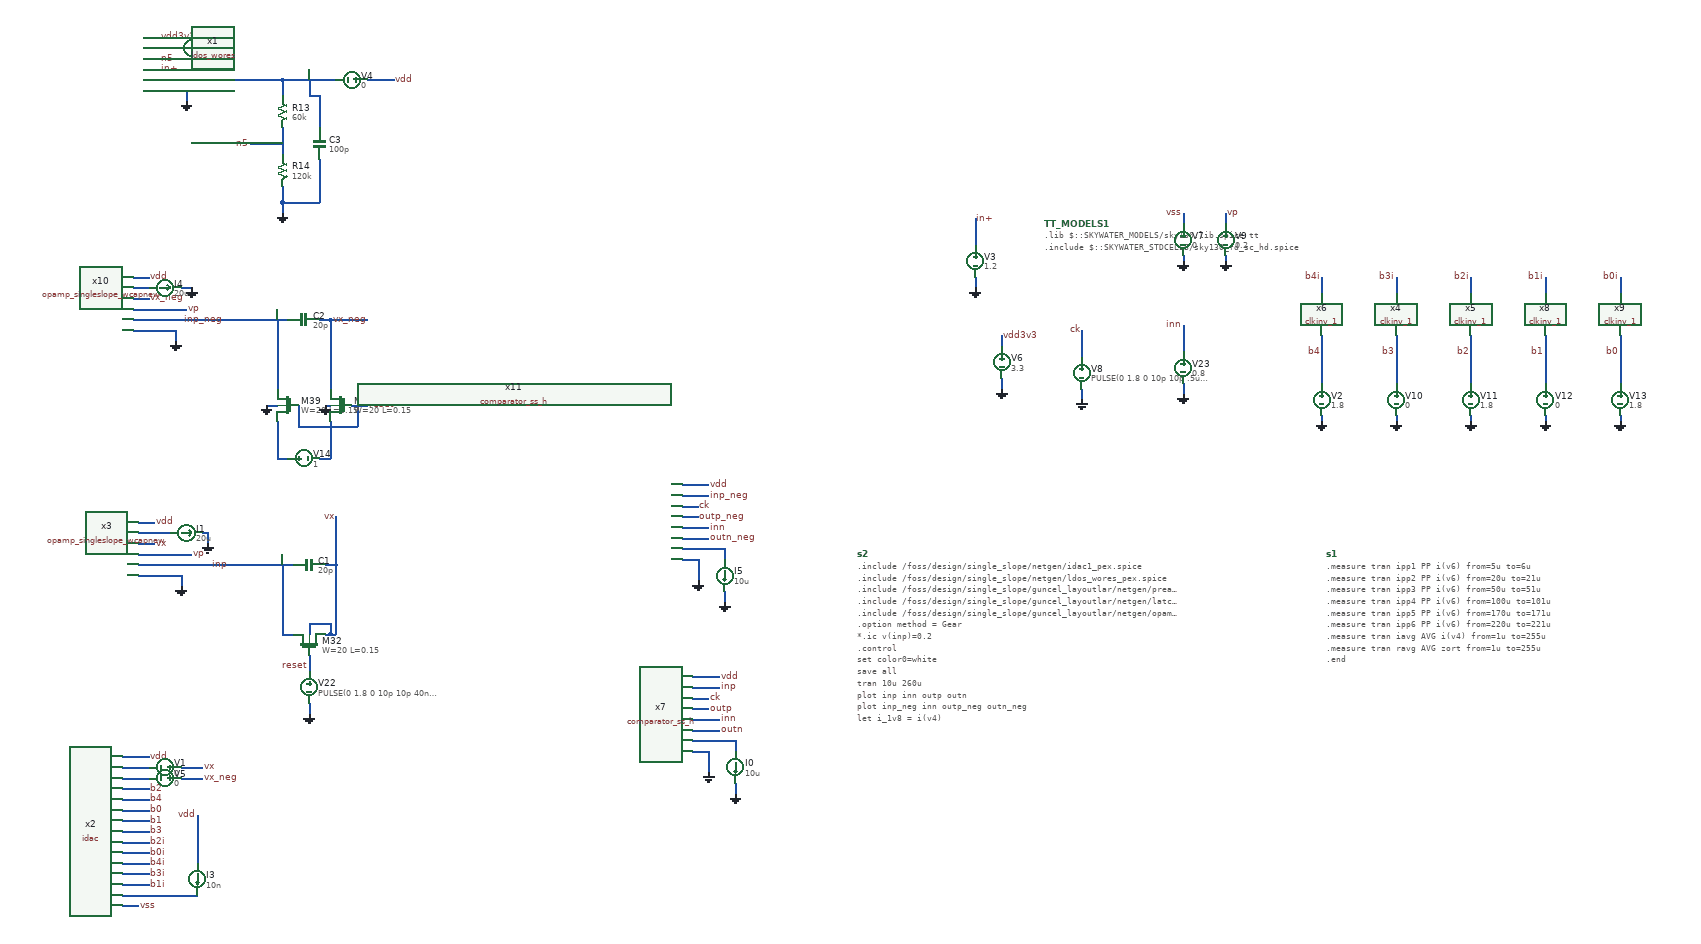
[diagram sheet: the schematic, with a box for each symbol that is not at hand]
v {xschem version=3.0.0 file_version=1.2 }
G {}
K {}
V {}
S {}
E {}
N 2560 -1410 2560 -1400 {
lab=GND}
N 2560 -1490 2560 -1470 {
lab=vp}
N 2480 -1410 2480 -1400 {
lab=GND}
N 2480 -1490 2480 -1470 {
lab=vss}
N 870 -830 890 -830 {
lab=vx}
N 730 -830 810 -830 {
lab=inp}
N 790 -700 810 -700 {
lab=inp}
N 790 -830 790 -700 {
lab=inp}
N 870 -700 880 -700 {
lab=vx}
N 880 -700 890 -700 {
lab=vx}
N 890 -830 890 -700 {
lab=vx}
N 840 -720 840 -700 {
lab=vx}
N 840 -720 880 -720 {
lab=vx}
N 880 -720 880 -700 {
lab=vx}
N 840 -660 840 -630 {
lab=reset}
N 840 -570 840 -550 {
lab=GND}
N 630 -830 730 -830 {
lab=inp}
N 520 -910 550 -910 {
lab=vdd}
N 520 -870 550 -870 {
lab=vx}
N 520 -850 600 -850 {
lab=vp}
N 520 -830 540 -830 {
lab=inp}
N 520 -810 600 -810 {
lab=GND}
N 600 -810 600 -790 {
lab=GND}
N 540 -830 630 -830 {
lab=inp}
N 600 -850 620 -850 {
lab=vp}
N 650 -890 650 -870 {
lab=GND}
N 520 -890 580 -890 {
lab=#net1}
N 640 -890 650 -890 {
lab=GND}
N 1590 -480 1590 -440 {
lab=GND}
N 1560 -600 1610 -600 {
lab=inp}
N 1560 -540 1610 -540 {
lab=inn}
N 1560 -520 1610 -520 {
lab=outn}
N 1560 -580 1590 -580 {
lab=ck}
N 1560 -560 1590 -560 {
lab=outp}
N 1560 -620 1610 -620 {
lab=vdd}
N 1560 -480 1590 -480 {
lab=GND}
N 1640 -500 1640 -480 {
lab=#net2}
N 1640 -420 1640 -400 {
lab=GND}
N 1560 -500 1640 -500 {
lab=#net2}
N 2290 -1160 2290 -1140 {
lab=GND}
N 2290 -1270 2290 -1220 {
lab=ck}
N 2480 -1170 2480 -1150 {
lab=GND}
N 2480 -1280 2480 -1230 {
lab=inn}
N 2090 -1450 2090 -1430 {
lab=in+}
N 2090 -1370 2090 -1350 {
lab=GND}
N 2090 -1460 2090 -1450 {
lab=in+}
N 2090 -1470 2090 -1460 {
lab=in+}
N 2090 -1480 2090 -1470 {
lab=in+}
N 790 -1510 790 -1490 {
lab=GND}
N 790 -1650 790 -1600 {
lab=n5}
N 790 -1740 790 -1710 {
lab=#net3}
N 790 -1740 890 -1740 {
lab=#net3}
N 790 -1540 790 -1510 {
lab=GND}
N 730 -1620 790 -1620 {
lab=n5}
N 950 -1740 1000 -1740 {
lab=vdd}
N 890 -840 890 -830 {
lab=vx}
N 890 -920 890 -840 {
lab=vx}
N 860 -1710 860 -1650 {
lab=#net3}
N 840 -1710 860 -1710 {
lab=#net3}
N 840 -1740 840 -1710 {
lab=#net3}
N 860 -1590 860 -1510 {
lab=GND}
N 790 -1510 860 -1510 {
lab=GND}
N 530 -1820 560 -1820 {
lab=vdd3v3}
N 530 -1780 560 -1780 {
lab=n5}
N 530 -1740 550 -1740 {
lab=#net3}
N 530 -1720 610 -1720 {
lab=GND}
N 610 -1720 610 -1700 {
lab=GND}
N 660 -1800 660 -1780 {
lab=GND}
N 530 -1800 590 -1800 {
lab=#net4}
N 650 -1800 660 -1800 {
lab=GND}
N 530 -1760 560 -1760 {
lab=in+}
N 550 -1740 560 -1740 {
lab=#net3}
N 560 -1740 680 -1740 {
lab=#net3}
N 2140 -1180 2140 -1160 {
lab=GND}
N 2140 -1260 2140 -1240 {
lab=vdd3v3}
N 680 -1740 730 -1740 {
lab=#net3}
N 730 -1740 790 -1740 {
lab=#net3}
N 490 -470 540 -470 {
lab=vdd}
N 490 -430 540 -430 {
lab=#net5}
N 490 -450 540 -450 {
lab=#net6}
N 490 -190 520 -190 {
lab=vss}
N 490 -410 540 -410 {
lab=b2}
N 490 -390 540 -390 {
lab=b4}
N 490 -370 540 -370 {
lab=b0}
N 490 -350 540 -350 {
lab=b1}
N 490 -330 540 -330 {
lab=b3}
N 490 -310 540 -310 {
lab=b2i}
N 490 -290 540 -290 {
lab=b0i}
N 490 -270 540 -270 {
lab=b4i}
N 490 -250 540 -250 {
lab=b3i}
N 490 -230 540 -230 {
lab=b1i}
N 490 -210 540 -210 {
lab=#net7}
N 630 -300 630 -270 {
lab=vdd}
N 630 -340 630 -300 {
lab=vdd}
N 630 -360 630 -340 {
lab=vdd}
N 540 -210 630 -210 {
lab=#net7}
N 610 -450 640 -450 {
lab=vx}
N 600 -450 610 -450 {
lab=vx}
N 600 -430 640 -430 {
lab=vx_neg}
N 2740 -1260 2740 -1230 {
lab=b4}
N 3160 -1260 3160 -1230 {
lab=b1}
N 3020 -1260 3020 -1230 {
lab=b2}
N 2880 -1260 2880 -1230 {
lab=b3}
N 3300 -1260 3300 -1230 {
lab=b0}
N 2740 -1370 2740 -1340 {
lab=b4i}
N 2880 -1370 2880 -1340 {
lab=b3i}
N 3020 -1370 3020 -1340 {
lab=b2i}
N 3160 -1370 3160 -1340 {
lab=b1i}
N 3300 -1370 3300 -1340 {
lab=b0i}
N 2740 -1110 2740 -1100 {
lab=GND}
N 2740 -1180 2740 -1170 {
lab=b4}
N 2880 -1110 2880 -1100 {
lab=GND}
N 3020 -1110 3020 -1100 {
lab=GND}
N 3160 -1110 3160 -1100 {
lab=GND}
N 3300 -1110 3300 -1100 {
lab=GND}
N 3020 -1180 3020 -1170 {
lab=b2}
N 2880 -1180 2880 -1170 {
lab=b3}
N 3300 -1180 3300 -1170 {
lab=b0}
N 3020 -1190 3020 -1180 {
lab=b2}
N 2880 -1190 2880 -1180 {
lab=b3}
N 3300 -1190 3300 -1180 {
lab=b0}
N 2740 -1230 2740 -1200 {
lab=b4}
N 3160 -1230 3160 -1200 {
lab=b1}
N 3020 -1200 3020 -1190 {
lab=b2}
N 2880 -1200 2880 -1190 {
lab=b3}
N 3020 -1230 3020 -1200 {
lab=b2}
N 2880 -1230 2880 -1200 {
lab=b3}
N 3300 -1200 3300 -1190 {
lab=b0}
N 3300 -1230 3300 -1200 {
lab=b0}
N 3160 -1200 3160 -1170 {
lab=b1}
N 2740 -1200 2740 -1180 {
lab=b4}
N 860 -1290 880 -1290 {
lab=vx_neg}
N 720 -1290 800 -1290 {
lab=inp_neg}
N 780 -1290 780 -1160 {
lab=inp_neg}
N 880 -1290 880 -1160 {
lab=vx_neg}
N 620 -1290 720 -1290 {
lab=inp_neg}
N 510 -1350 540 -1350 {
lab=#net8}
N 510 -1330 540 -1330 {
lab=vx_neg}
N 510 -1310 590 -1310 {
lab=vp}
N 510 -1290 530 -1290 {
lab=inp_neg}
N 510 -1270 590 -1270 {
lab=GND}
N 590 -1270 590 -1250 {
lab=GND}
N 530 -1290 620 -1290 {
lab=inp_neg}
N 590 -1310 610 -1310 {
lab=vp}
N 780 -1030 800 -1030 {
lab=#net9}
N 860 -1030 880 -1030 {
lab=#net10}
N 780 -1100 780 -1030 {
lab=#net9}
N 880 -1100 880 -1030 {
lab=#net10}
N 760 -1130 780 -1130 {
lab=GND}
N 870 -1130 880 -1130 {
lab=GND}
N 920 -1130 950 -1130 {
lab=reset}
N 820 -1130 820 -1090 {
lab=reset}
N 820 -1090 930 -1090 {
lab=reset}
N 930 -1130 930 -1090 {
lab=reset}
N 880 -1290 950 -1290 {
lab=vx_neg}
N 510 -1370 540 -1370 {
lab=vdd}
N 600 -1350 620 -1350 {
lab=GND}
N 1570 -840 1570 -800 {
lab=GND}
N 1540 -960 1590 -960 {
lab=inp_neg}
N 1540 -900 1590 -900 {
lab=inn}
N 1540 -880 1590 -880 {
lab=outn_neg}
N 1540 -940 1570 -940 {
lab=ck}
N 1540 -920 1570 -920 {
lab=outp_neg}
N 1540 -980 1590 -980 {
lab=vdd}
N 1540 -840 1570 -840 {
lab=GND}
N 1620 -860 1620 -840 {
lab=#net11}
N 1620 -780 1620 -760 {
lab=GND}
N 1540 -860 1620 -860 {
lab=#net11}
C {devices/code_shown.sym} 1870 -850 0 0 {name=s2 only_toplevel=false value="

.include /foss/design/single_slope/netgen/idac1_pex.spice
.include /foss/design/single_slope/netgen/ldos_wores_pex.spice
.include /foss/design/single_slope/guncel_layoutlar/netgen/preamp_singleslope_new_pex.spice
.include /foss/design/single_slope/guncel_layoutlar/netgen/latch_singleslope_new_pex.spice
.include /foss/design/single_slope/guncel_layoutlar/netgen/opamp_singleslope_addcap_pex.spice
.option method = Gear
*.ic v(inp)=0.2

.control
set color0=white
save all

tran 10u 260u
plot inp inn outp outn
plot inp_neg inn outp_neg outn_neg
let i_1v8 = i(v4)
let i_3v3 = i(v6)
let zort = vdd/i(v4)
plot i_1v8 i_3v3
plot v(vdd)
plot vdd3v3
plot i_1v8
plot i_3v3
plot inp inp_neg outp outp_neg

*show all
.endc
.end
"
}
C {devices/code.sym} 2220 -1470 0 0 {name=TT_MODELS1
only_toplevel=true
format="tcleval(@value )"
value=".lib $::SKYWATER_MODELS/sky130.lib.spice tt
.include $::SKYWATER_STDCELLS/sky130_fd_sc_hd.spice
"
spice_ignore=false
place=header}
C {devices/vsource.sym} 2560 -1440 0 0 {name=V9 value=0.2}
C {devices/gnd.sym} 2560 -1400 0 1 {name=l5 lab=GND}
C {devices/vsource.sym} 2480 -1440 0 0 {name=V7 value=0}
C {devices/gnd.sym} 2480 -1400 0 1 {name=l53 lab=GND}
C {devices/lab_pin.sym} 2480 -1490 0 0 {name=l54 sig_type=std_logic lab=vss}
C {devices/lab_pin.sym} 2560 -1490 2 0 {name=l59 sig_type=std_logic lab=vp}
C {devices/capa.sym} 840 -830 1 0 {name=C1
m=1
value=20p
footprint=1206
device="ceramic capacitor"}
C {pdk/sky130A/libs.tech/xschem/sky130_fd_pr/nfet_01v8.sym} 840 -680 3 0 {name=M32
L=0.15
W=20
nf=1 
mult=2
ad="'int((nf+1)/2) * W/nf * 0.29'" 
pd="'2*int((nf+1)/2) * (W/nf + 0.29)'"
as="'int((nf+2)/2) * W/nf * 0.29'" 
ps="'2*int((nf+2)/2) * (W/nf + 0.29)'"
nrd="'0.29 / W'" nrs="'0.29 / W'"
sa=0 sb=0 sd=0
model=nfet_01v8
spiceprefix=X
}
C {devices/vsource.sym} 840 -600 0 0 {name=V22 value="PULSE(0 1.8 0 10p 10p 40n 256.04u)"}
C {devices/gnd.sym} 840 -550 0 0 {name=l81 lab=GND}
C {devices/lab_pin.sym} 550 -910 2 0 {name=l82 sig_type=std_logic lab=vdd}
C {devices/lab_pin.sym} 840 -640 0 0 {name=l83 sig_type=std_logic lab=reset}
C {devices/lab_pin.sym} 550 -870 2 0 {name=l84 sig_type=std_logic lab=vx}
C {devices/gnd.sym} 600 -790 0 0 {name=l85 lab=GND}
C {devices/lab_pin.sym} 690 -830 1 0 {name=l86 sig_type=std_logic lab=inp}
C {devices/isource.sym} 610 -890 3 0 {name=I1 value=20u}
C {devices/gnd.sym} 650 -870 0 0 {name=l87 lab=GND}
C {design/single_slope/opamp_singleslope_wcapnew.sym} 370 -860 0 0 {name=x3}
C {devices/lab_pin.sym} 620 -850 0 1 {name=l88 sig_type=std_logic lab=vp}
C {devices/gnd.sym} 1590 -440 0 0 {name=l76 lab=GND}
C {devices/lab_pin.sym} 1610 -620 0 1 {name=l79 sig_type=std_logic lab=vdd}
C {devices/lab_pin.sym} 1590 -580 0 1 {name=l107 sig_type=std_logic lab=ck}
C {devices/lab_pin.sym} 1610 -600 0 1 {name=l108 sig_type=std_logic lab=inp}
C {devices/lab_pin.sym} 1610 -540 0 1 {name=l109 sig_type=std_logic lab=inn}
C {devices/lab_pin.sym} 1590 -560 0 1 {name=l110 sig_type=std_logic lab=outp}
C {devices/lab_pin.sym} 1610 -520 0 1 {name=l111 sig_type=std_logic lab=outn}
C {devices/isource.sym} 1640 -450 0 0 {name=I0 value=10u}
C {devices/gnd.sym} 1640 -400 0 0 {name=l112 lab=GND}
C {design/single_slope/comparator_ss_h.sym} 1410 -550 0 0 {name=x7}
C {devices/vsource.sym} 2290 -1190 0 0 {name=V8 value="PULSE(0 1.8 0 10p 10p .5u 1u)"
}
C {devices/gnd.sym} 2290 -1140 0 0 {name=l123 lab=GND}
C {devices/lab_pin.sym} 2290 -1270 0 0 {name=l124 sig_type=std_logic lab=ck}
C {devices/vsource.sym} 2480 -1200 0 0 {name=V23 value=0.8}
C {devices/gnd.sym} 2480 -1150 0 0 {name=l125 lab=GND}
C {devices/lab_pin.sym} 2480 -1280 0 0 {name=l126 sig_type=std_logic lab=inn}
C {devices/vsource.sym} 2090 -1400 0 0 {name=V3 value=1.2}
C {devices/gnd.sym} 2090 -1350 0 0 {name=l4 lab=GND}
C {devices/lab_pin.sym} 2090 -1480 2 0 {name=l24 sig_type=std_logic lab=in+}
C {devices/gnd.sym} 790 -1490 0 0 {name=l156 lab=GND}
C {devices/res.sym} 790 -1680 0 0 {name=R13
value=60k
footprint=1206
device=resistor
m=1}
C {devices/res.sym} 790 -1570 0 0 {name=R14
value=120k
footprint=1206
device=resistor
m=1}
C {devices/lab_pin.sym} 730 -1620 0 0 {name=l100 sig_type=std_logic lab=n5}
C {devices/lab_pin.sym} 1000 -1740 0 1 {name=l101 sig_type=std_logic lab=vdd}
C {devices/vsource.sym} 920 -1740 1 0 {name=V4 value=0}
C {devices/lab_pin.sym} 890 -920 1 0 {name=l6 sig_type=std_logic lab=vx}
C {devices/code_shown.sym} 2750 -850 0 0 {name=s1 only_toplevel=false value="

.measure tran ipp1 PP i(v6) from=5u to=6u
.measure tran ipp2 PP i(v6) from=20u to=21u
.measure tran ipp3 PP i(v6) from=50u to=51u
.measure tran ipp4 PP i(v6) from=100u to=101u
.measure tran ipp5 PP i(v6) from=170u to=171u
.measure tran ipp6 PP i(v6) from=220u to=221u
.measure tran iavg AVG i(v4) from=1u to=255u
.measure tran ravg AVG zort from=1u to=255u
.end
"
}
C {devices/capa.sym} 860 -1620 0 0 {name=C3
m=1
value=100p
footprint=1206
device="ceramic capacitor"}
C {devices/lab_pin.sym} 560 -1820 2 0 {name=l2 sig_type=std_logic lab=vdd3v3}
C {devices/lab_pin.sym} 560 -1780 2 0 {name=l3 sig_type=std_logic lab=n5}
C {devices/gnd.sym} 610 -1700 0 0 {name=l7 lab=GND}
C {devices/lab_pin.sym} 560 -1760 2 0 {name=l8 sig_type=std_logic lab=in+}
C {devices/isource.sym} 620 -1800 3 0 {name=I2 value=15u}
C {devices/gnd.sym} 660 -1780 0 0 {name=l9 lab=GND}
C {devices/vsource.sym} 2140 -1210 0 0 {name=V6 value=3.3}
C {devices/gnd.sym} 2140 -1160 0 0 {name=l11 lab=GND}
C {devices/lab_pin.sym} 2140 -1260 0 1 {name=l12 sig_type=std_logic lab=vdd3v3}
C {design/ldo/ldos_wores.sym} 380 -1770 0 0 {name=x1}
C {devices/lab_pin.sym} 540 -470 2 0 {name=l10 sig_type=std_logic lab=vdd}
C {devices/lab_pin.sym} 640 -450 2 0 {name=l13 sig_type=std_logic lab=vx}
C {devices/lab_pin.sym} 640 -430 2 0 {name=l14 sig_type=std_logic lab=vx_neg}
C {devices/lab_pin.sym} 520 -190 2 0 {name=l15 sig_type=std_logic lab=vss}
C {devices/lab_pin.sym} 540 -410 2 0 {name=l16 sig_type=std_logic lab=b2}
C {devices/lab_pin.sym} 540 -390 2 0 {name=l17 sig_type=std_logic lab=b4}
C {devices/lab_pin.sym} 540 -370 2 0 {name=l18 sig_type=std_logic lab=b0}
C {devices/lab_pin.sym} 540 -350 2 0 {name=l19 sig_type=std_logic lab=b1}
C {devices/lab_pin.sym} 540 -330 2 0 {name=l113 sig_type=std_logic lab=b3}
C {devices/lab_pin.sym} 540 -310 2 0 {name=l114 sig_type=std_logic lab=b2i}
C {devices/lab_pin.sym} 540 -290 2 0 {name=l115 sig_type=std_logic lab=b0i}
C {devices/lab_pin.sym} 540 -270 2 0 {name=l116 sig_type=std_logic lab=b4i}
C {devices/lab_pin.sym} 540 -250 2 0 {name=l117 sig_type=std_logic lab=b3i}
C {devices/lab_pin.sym} 540 -230 2 0 {name=l118 sig_type=std_logic lab=b1i}
C {devices/isource.sym} 630 -240 0 0 {name=I3 value=10n}
C {devices/lab_pin.sym} 630 -360 0 0 {name=l119 sig_type=std_logic lab=vdd}
C {devices/vsource.sym} 570 -450 1 0 {name=V1 value=0}
C {devices/vsource.sym} 570 -430 1 0 {name=V5 value=0}
C {design/single_slope/idac.sym} 350 -330 0 0 {name=x2}
C {pdk/sky130A/libs.tech/xschem/sky130_stdcells/clkinv_1.sym} 2740 -1300 3 0 {name=x6 VGND=vss VNB=vss VPB=vdd VPWR=vdd prefix=sky130_fd_sc_hd__ }
C {devices/lab_pin.sym} 2740 -1370 0 0 {name=p6 sig_type=std_logic lab=b4i
}
C {devices/lab_pin.sym} 2880 -1370 0 0 {name=p7 sig_type=std_logic lab=b3i
}
C {devices/lab_pin.sym} 3020 -1370 0 0 {name=p8 sig_type=std_logic lab=b2i
}
C {devices/lab_pin.sym} 3160 -1370 0 0 {name=p9 sig_type=std_logic lab=b1i
}
C {devices/lab_pin.sym} 3300 -1370 0 0 {name=p16 sig_type=std_logic lab=b0i
}
C {pdk/sky130A/libs.tech/xschem/sky130_stdcells/clkinv_1.sym} 2880 -1300 3 0 {name=x4 VGND=vss VNB=vss VPB=vdd VPWR=vdd prefix=sky130_fd_sc_hd__ }
C {pdk/sky130A/libs.tech/xschem/sky130_stdcells/clkinv_1.sym} 3020 -1300 3 0 {name=x5 VGND=vss VNB=vss VPB=vdd VPWR=vdd prefix=sky130_fd_sc_hd__ }
C {pdk/sky130A/libs.tech/xschem/sky130_stdcells/clkinv_1.sym} 3160 -1300 3 0 {name=x8 VGND=vss VNB=vss VPB=vdd VPWR=vdd prefix=sky130_fd_sc_hd__ }
C {pdk/sky130A/libs.tech/xschem/sky130_stdcells/clkinv_1.sym} 3300 -1300 3 0 {name=x9 VGND=vss VNB=vss VPB=vdd VPWR=vdd prefix=sky130_fd_sc_hd__ }
C {devices/vsource.sym} 2740 -1140 0 0 {name=V2 value= 1.8
*"PULSE(1.8 0 0 1n 1n 4096u 8192u)" savecurrent=false}
C {devices/gnd.sym} 2740 -1100 0 1 {name=l1 lab=GND}
C {devices/gnd.sym} 2880 -1100 0 1 {name=l20 lab=GND}
C {devices/gnd.sym} 3020 -1100 0 1 {name=l25 lab=GND}
C {devices/gnd.sym} 3160 -1100 0 1 {name=l26 lab=GND}
C {devices/gnd.sym} 3300 -1100 0 1 {name=l27 lab=GND}
C {devices/lab_pin.sym} 2740 -1230 0 0 {name=p11 sig_type=std_logic lab=b4
}
C {devices/vsource.sym} 2880 -1140 0 0 {name=V10 value= 0
*"PULSE(1.8 0 0 1n 1n 2048u 4096u)" savecurrent=false}
C {devices/vsource.sym} 3020 -1140 0 0 {name=V11 value=1.8
*"PULSE(1.8 0 0 1n 1n 1024u 2048u)" savecurrent=false}
C {devices/vsource.sym} 3160 -1140 0 0 {name=V12 value=0
*"PULSE(1.8 0 0 1n 1n 512u 1024u)" savecurrent=false}
C {devices/vsource.sym} 3300 -1140 0 0 {name=V13 value=1.8
*"PULSE(1.8 0 0 1n 1n 256u 512u)" savecurrent=false}
C {devices/lab_pin.sym} 3160 -1230 0 0 {name=p12 sig_type=std_logic lab=b1
}
C {devices/lab_pin.sym} 2880 -1230 0 0 {name=p13 sig_type=std_logic lab=b3
}
C {devices/lab_pin.sym} 3020 -1230 0 0 {name=p14 sig_type=std_logic lab=b2
}
C {devices/lab_pin.sym} 3300 -1230 0 0 {name=p15 sig_type=std_logic lab=b0
}
C {devices/capa.sym} 830 -1290 1 0 {name=C2
m=1
value=20p
footprint=1206
device="ceramic capacitor"}
C {devices/lab_pin.sym} 950 -1290 1 0 {name=l97 sig_type=std_logic lab=vx_neg}
C {devices/lab_pin.sym} 540 -1370 2 0 {name=l98 sig_type=std_logic lab=vdd}
C {devices/lab_pin.sym} 540 -1330 2 0 {name=l99 sig_type=std_logic lab=vx_neg}
C {devices/gnd.sym} 590 -1250 0 0 {name=l21 lab=GND}
C {devices/lab_pin.sym} 680 -1290 1 0 {name=l22 sig_type=std_logic lab=inp_neg}
C {devices/vsource.sym} 830 -1030 3 0 {name=V14 value=1}
C {devices/lab_pin.sym} 950 -1130 0 1 {name=l102 sig_type=std_logic lab=reset}
C {pdk/sky130A/libs.tech/xschem/sky130_fd_pr/nfet_01v8.sym} 800 -1130 2 0 {name=M39
L=0.15
W=20
nf=1 
mult=2
ad="'int((nf+1)/2) * W/nf * 0.29'" 
pd="'2*int((nf+1)/2) * (W/nf + 0.29)'"
as="'int((nf+2)/2) * W/nf * 0.29'" 
ps="'2*int((nf+2)/2) * (W/nf + 0.29)'"
nrd="'0.29 / W'" nrs="'0.29 / W'"
sa=0 sb=0 sd=0
model=nfet_01v8
spiceprefix=X
}
C {pdk/sky130A/libs.tech/xschem/sky130_fd_pr/nfet_01v8.sym} 900 -1130 2 0 {name=M40
L=0.15
W=20
nf=1 
mult=2
ad="'int((nf+1)/2) * W/nf * 0.29'" 
pd="'2*int((nf+1)/2) * (W/nf + 0.29)'"
as="'int((nf+2)/2) * W/nf * 0.29'" 
ps="'2*int((nf+2)/2) * (W/nf + 0.29)'"
nrd="'0.29 / W'" nrs="'0.29 / W'"
sa=0 sb=0 sd=0
model=nfet_01v8
spiceprefix=X
}
C {devices/gnd.sym} 760 -1130 0 0 {name=l103 lab=GND}
C {devices/gnd.sym} 870 -1130 0 0 {name=l104 lab=GND}
C {devices/lab_pin.sym} 610 -1310 0 1 {name=l105 sig_type=std_logic lab=vp}
C {design/single_slope/opamp_singleslope_wcapnew.sym} 360 -1320 0 0 {name=x10}
C {devices/isource.sym} 570 -1350 3 0 {name=I4 value=20u}
C {devices/gnd.sym} 620 -1350 0 0 {name=l106 lab=GND}
C {devices/gnd.sym} 1570 -800 0 0 {name=l23 lab=GND}
C {devices/lab_pin.sym} 1590 -980 0 1 {name=l28 sig_type=std_logic lab=vdd}
C {devices/lab_pin.sym} 1570 -940 0 1 {name=l29 sig_type=std_logic lab=ck}
C {devices/lab_pin.sym} 1590 -960 0 1 {name=l30 sig_type=std_logic lab=inp_neg}
C {devices/lab_pin.sym} 1590 -900 0 1 {name=l31 sig_type=std_logic lab=inn}
C {devices/lab_pin.sym} 1570 -920 0 1 {name=l32 sig_type=std_logic lab=outp_neg}
C {devices/lab_pin.sym} 1590 -880 0 1 {name=l37 sig_type=std_logic lab=outn_neg}
C {devices/isource.sym} 1620 -810 0 0 {name=I5 value=10u}
C {devices/gnd.sym} 1620 -760 0 0 {name=l38 lab=GND}
C {design/single_slope/comparator_ss_h.sym} 1390 -910 0 0 {name=x11}
